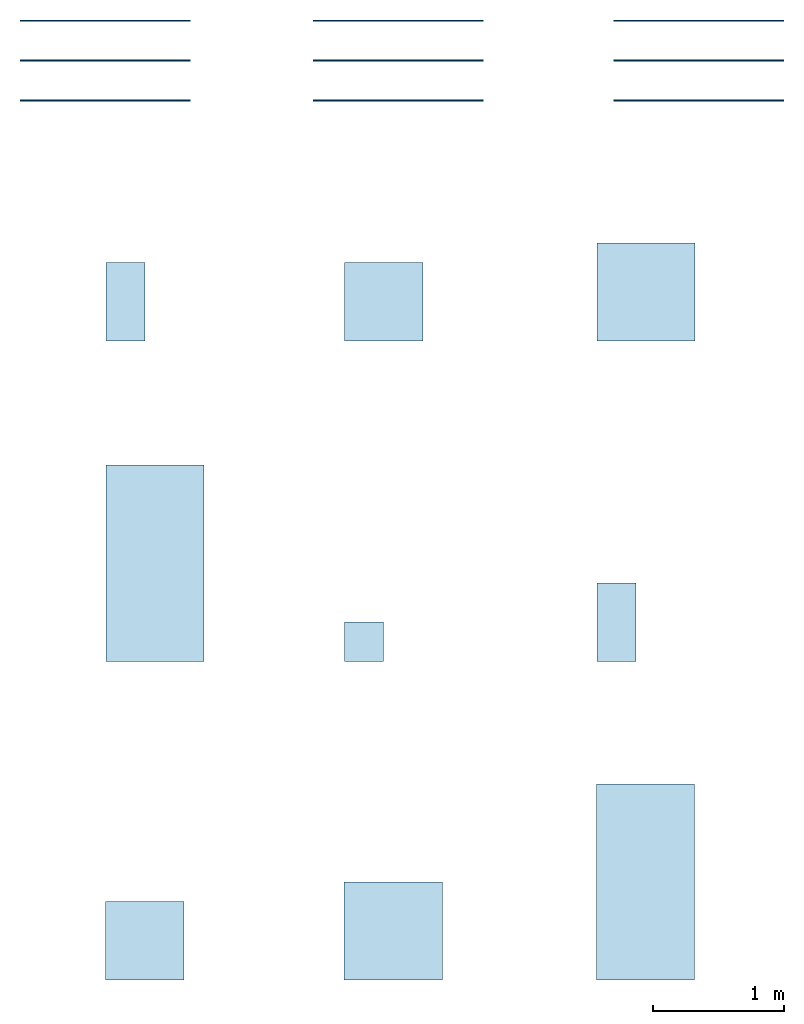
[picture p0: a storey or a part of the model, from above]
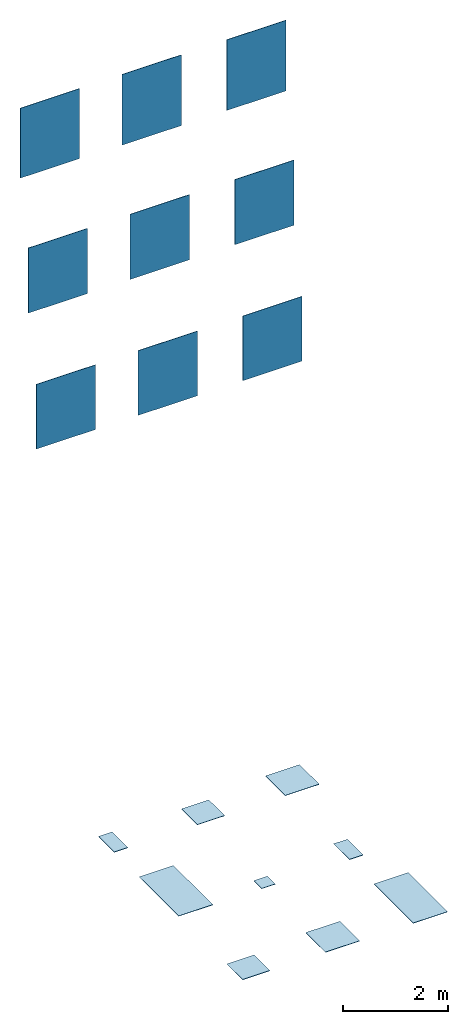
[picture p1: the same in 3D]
Properties of the parts of a building model (IFC2X3)

# File
Description: ViewDefinition [CoordinationView_V2.0]
File name: Project Number
Time: 2021-09-16T11:53:30
Written by: The EXPRESS Data Manager Version 5.02.0100.07 : 28 Aug 2013
Made in: 20190808_0900(x64) - Exporter 19.5.0.0 - Alternate UI 19.5.0.0
Comment: STEP Physical File produced by: The EXPRESS Data Manager Version 5.02.0100.07 : 28 Aug 2013 * Module: EDMstepFileFactory/EDMstandAlone * Creation date: Thu Sep 16 11:53:30 2021 * Host: Davide1988 * Database: C:\Users\DAVIDE~1\AppData\Local\Temp\{9264C9B8-D94B-46D0-A2EC-CCEAC0D1AFE5}\ifc * Database version: 5507 * Database creation date: Thu Sep 16 11:53:26 2021 * Schema: IFC2X3 * Model: DataRepository.ifc * Model creation date: Thu Sep 16 11:53:26 2021 * Header model: DataRepository.ifc_HeaderModel * Header model creation date: Thu Sep 16 11:53:26 2021 * EDMuser: sdai-user * EDMgroup: sdai-group * License ID and type: 5605 : Permanent license. Expiry date: * EDMstepFileFactory options: 020000

# IfcProject, Project Number
LongName: Refin-Blended; Phase: Project Status

# IfcSite, Default
RefLatitude: 51, 30, 0, 549316; RefLongitude: 0, -7, -34, -450321; RefElevation: 0 mm
Pset_ProductRequirements - Category: Project Information

# IfcBuilding
Pset_BuildingCommon - NumberOfStoreys: 1
Pset_ProductRequirements - Category: Project Information

# IfcBuildingStorey: Level:Circle Head - Project Datum, Level 0
LongName: Level 0; Elevation: 0 mm
Pset_AirSideSystemInformation - Name: Level 0
Pset_ProductRequirements - Name: Level 0; Category: Levels

# IfcSlab: Floor:Floor_Tiles_Refin-Prestigio_Onyx-Beige-30x30 NZ91, Floor:Floor_Tiles_Refin-Prestigio_Onyx-Beige-30x30 NZ91:304948
In: Level 0
Type - PredefinedType: FLOOR; Material: Prestigio Onyx-Beige-30x30 NZ91 9 mm, <Unnamed> 1 mm
Type - Pset_ConcreteElementGeneral - FireRating: INERT
Type - Pset_ElementShading - Roughness: 914.4 mm; Color: WHITE
Type - Pset_FireRatingProperties - SurfaceSpreadOfFlame: INERT
Type - Pset_ManufacturerOccurrence - BarCode: N/A; SerialNumber: N/A
Type - Pset_ManufacturerTypeInformation - ArticleNumber: NZ91; ModelReference: NZ91; ModelLabel: BEIGE MOSAICO T LUCIDO R 30X30; Manufacturer: info@refin.it; ProductionYear: N/A
Type - Pset_PrecastConcreteElementGeneral - SerialNumber: N/A
Type - Pset_ProductRequirements - Name: Prestigio Onyx_Beige_Mosaico_T_Lucido_30X30 R; Category: Pr_35_93_96_19:Ceramic tiles
Type - Pset_QuantityTakeOff - Reference: N/A
Type - Pset_ReinforcementBarPitchOfSlab - Description: PORCELAIN STONEWARE TILE; Reference: N/A
Type - Pset_SlabCommon - Reference: N/A; IsExternal: no; AcousticRating: N/A; FireRating: INERT; SurfaceSpreadOfFlame: INERT
Type - Pset_Warranty - WarrantyContent: N/A; Exclusions: N/A
Pset_ProductRequirements - Category: Floors
Pset_SlabCommon - LoadBearing: no; PitchAngle: 0 deg

# IfcSlab: Floor:Floor_Tiles_Refin-Prestigio_Onyx-Beige-30x60 NW01, Floor:Floor_Tiles_Refin-Prestigio_Onyx-Beige-30x60 NW01:304668
In: Level 0
Type - PredefinedType: FLOOR; Material: Prestigio Onyx-Beige-30x60 NW01 9 mm, <Unnamed> 1 mm
Type - Pset_ConcreteElementGeneral - FireRating: INERT
Type - Pset_ElementShading - Roughness: 914.4 mm; Color: IVORY-BEIGE
Type - Pset_FireRatingProperties - SurfaceSpreadOfFlame: INERT
Type - Pset_ManufacturerOccurrence - BarCode: N/A; SerialNumber: N/A
Type - Pset_ManufacturerTypeInformation - ArticleNumber: NW01; ModelReference: NW01; ModelLabel: BEIGE LUCIDO R 30X60; Manufacturer: info@refin.it; ProductionYear: N/A
Type - Pset_PrecastConcreteElementGeneral - SerialNumber: N/A
Type - Pset_ProductRequirements - Name: Prestigio Onyx_Beige_Lucido_30X60 R; Category: Pr_35_93_96_19:Ceramic tiles
Type - Pset_QuantityTakeOff - Reference: N/A
Type - Pset_ReinforcementBarPitchOfSlab - Description: PORCELAIN STONEWARE TILE; Reference: N/A
Type - Pset_SlabCommon - Reference: N/A; IsExternal: no; AcousticRating: N/A; FireRating: INERT; SurfaceSpreadOfFlame: INERT
Type - Pset_Warranty - WarrantyContent: N/A; Exclusions: N/A
Pset_ProductRequirements - Category: Floors
Pset_SlabCommon - LoadBearing: no; PitchAngle: 0 deg

# IfcSlab: Floor:Floor_Tiles_Refin-Prestigio_Onyx-Beige-60x60 NZ95, Floor:Floor_Tiles_Refin-Prestigio_Onyx-Beige-60x60 NZ95:324498
In: Level 0
Type - PredefinedType: FLOOR; Material: Prestigio Onyx-Beige-60x60 NZ95 9 mm, <Unnamed> 1 mm
Type - Pset_ConcreteElementGeneral - FireRating: INERT
Type - Pset_ElementShading - Roughness: 914.4 mm; Color: IVORY-BEIGE
Type - Pset_FireRatingProperties - SurfaceSpreadOfFlame: INERT
Type - Pset_ManufacturerOccurrence - BarCode: N/A; SerialNumber: N/A
Type - Pset_ManufacturerTypeInformation - ArticleNumber: NZ95; ModelReference: NZ95; ModelLabel: BEIGE LUCIDO R 60X60; Manufacturer: info@refin.it; ProductionYear: N/A
Type - Pset_PrecastConcreteElementGeneral - SerialNumber: N/A
Type - Pset_ProductRequirements - Name: Prestigio_Onyx_Beige_Lucido_60X60 R; Category: Pr_35_93_96_19:Ceramic tiles
Type - Pset_QuantityTakeOff - Reference: N/A
Type - Pset_ReinforcementBarPitchOfSlab - Description: PORCELAIN STONEWARE TILE; Reference: N/A
Type - Pset_SlabCommon - Reference: N/A; IsExternal: no; AcousticRating: N/A; FireRating: INERT; SurfaceSpreadOfFlame: INERT
Type - Pset_Warranty - WarrantyContent: N/A; Exclusions: N/A
Pset_ProductRequirements - Category: Floors
Pset_SlabCommon - LoadBearing: no; PitchAngle: 0 deg

# IfcSlab: Floor:Floor_Tiles_Refin-Prestigio_Onyx-Beige-75x150 NV71, Floor:Floor_Tiles_Refin-Prestigio_Onyx-Beige-75x150 NV71:304956
In: Level 0
Type - PredefinedType: FLOOR; Material: Prestigio Onyx-Beige-75x150 NV71 9 mm, <Unnamed> 1 mm
Type - Pset_ConcreteElementGeneral - FireRating: INERT
Type - Pset_ElementShading - Roughness: 914.4 mm; Color: IVORY-BEIGE
Type - Pset_FireRatingProperties - SurfaceSpreadOfFlame: INERT
Type - Pset_ManufacturerOccurrence - BarCode: N/A; SerialNumber: N/A
Type - Pset_ManufacturerTypeInformation - ArticleNumber: NV71; ModelReference: NV71; ModelLabel: BEIGE LUCIDO R 75X150; Manufacturer: info@refin.it; ProductionYear: N/A
Type - Pset_PrecastConcreteElementGeneral - SerialNumber: N/A
Type - Pset_ProductRequirements - Name: Prestigio_Onyx_Beige_Lucido_75X150 R; Category: Pr_35_93_96_19:Ceramic tiles
Type - Pset_QuantityTakeOff - Reference: N/A
Type - Pset_ReinforcementBarPitchOfSlab - Description: PORCELAIN STONEWARE TILE; Reference: N/A
Type - Pset_SlabCommon - Reference: N/A; IsExternal: no; AcousticRating: N/A; FireRating: INERT; SurfaceSpreadOfFlame: INERT
Type - Pset_Warranty - WarrantyContent: N/A; Exclusions: N/A
Pset_ProductRequirements - Category: Floors
Pset_SlabCommon - LoadBearing: no; PitchAngle: 0 deg

# IfcSlab: Floor:Floor_Tiles_Refin-Prestigio_Onyx-Beige-75x75 NZ83, Floor:Floor_Tiles_Refin-Prestigio_Onyx-Beige-75x75 NZ83:285295
In: Level 0
Type - PredefinedType: FLOOR; Material: Prestigio Onyx-Beige-75x75 NZ83 9 mm, <Unnamed> 1 mm
Type - Pset_ConcreteElementGeneral - FireRating: INERT
Type - Pset_ElementShading - Roughness: 914.4 mm; Color: WHITE
Type - Pset_FireRatingProperties - SurfaceSpreadOfFlame: INERT
Type - Pset_ManufacturerOccurrence - BarCode: N/A; SerialNumber: N/A
Type - Pset_ManufacturerTypeInformation - ArticleNumber: NZ83; ModelReference: NZ83; ModelLabel: BEIGE LUCIDO R 75X75; Manufacturer: info@refin.it; ProductionYear: N/A
Type - Pset_PrecastConcreteElementGeneral - SerialNumber: N/A
Type - Pset_ProductRequirements - Name: Prestigio Onyx_Beige_Lucido_75X75 R; Category: Pr_35_93_96_19:Ceramic tiles
Type - Pset_QuantityTakeOff - Reference: N/A
Type - Pset_ReinforcementBarPitchOfSlab - Description: PORCELAIN STONEWARE TILE; Reference: N/A
Type - Pset_SlabCommon - Reference: N/A; IsExternal: no; AcousticRating: N/A; FireRating: INERT; SurfaceSpreadOfFlame: INERT
Type - Pset_Warranty - WarrantyContent: N/A; Exclusions: N/A
Pset_ProductRequirements - Category: Floors
Pset_SlabCommon - LoadBearing: no; PitchAngle: 0 deg

# IfcSlab: Floor:Floor_Tiles_Refin-Prestigio_Onyx-Beige_Soft-30x60 NW06, Floor:Floor_Tiles_Refin-Prestigio_Onyx-Beige_Soft-30x60 NW06:304932
In: Level 0
Type - PredefinedType: FLOOR; Material: Prestigio Onyx-Beige-Soft-30x60 NW06 9 mm, <Unnamed> 1 mm
Type - Pset_ConcreteElementGeneral - FireRating: INERT
Type - Pset_ElementShading - Roughness: 914.4 mm; Color: IVORY-BEIGE
Type - Pset_FireRatingProperties - SurfaceSpreadOfFlame: INERT
Type - Pset_ManufacturerOccurrence - BarCode: N/A; SerialNumber: N/A
Type - Pset_ManufacturerTypeInformation - ArticleNumber: NW06; ModelReference: NW06; ModelLabel: BEIGE SOFT R 30X60; Manufacturer: info@refin.it; ProductionYear: N/A
Type - Pset_PrecastConcreteElementGeneral - SerialNumber: N/A
Type - Pset_ProductRequirements - Name: Prestigio Onyx_Beige_Soft_30X60 R; Category: Pr_35_93_96_19:Ceramic tiles
Type - Pset_QuantityTakeOff - Reference: N/A
Type - Pset_ReinforcementBarPitchOfSlab - Description: PORCELAIN STONEWARE TILE; Reference: N/A
Type - Pset_SlabCommon - Reference: N/A; IsExternal: no; AcousticRating: N/A; FireRating: INERT; SurfaceSpreadOfFlame: INERT
Type - Pset_Warranty - WarrantyContent: N/A; Exclusions: N/A
Pset_ProductRequirements - Category: Floors
Pset_SlabCommon - LoadBearing: no; PitchAngle: 0 deg

# IfcSlab: Floor:Floor_Tiles_Refin-Prestigio_Onyx-Beige_Soft-60x60 NZ98, Floor:Floor_Tiles_Refin-Prestigio_Onyx-Beige_Soft-60x60 NZ98:305509
In: Level 0
Type - PredefinedType: FLOOR; Material: Prestigio Onyx-Beige-Soft-60x60 NZ98 9 mm, <Unnamed> 1 mm
Type - Pset_ConcreteElementGeneral - FireRating: INERT
Type - Pset_ElementShading - Roughness: 914.4 mm; Color: IVORY-BEIGE
Type - Pset_FireRatingProperties - SurfaceSpreadOfFlame: INERT
Type - Pset_ManufacturerOccurrence - BarCode: N/A; SerialNumber: N/A
Type - Pset_ManufacturerTypeInformation - ArticleNumber: NZ98; ModelReference: NZ98; ModelLabel: BEIGE SOFT R 60X60; Manufacturer: info@refin.it; ProductionYear: N/A
Type - Pset_PrecastConcreteElementGeneral - SerialNumber: N/A
Type - Pset_ProductRequirements - Name: Prestigio Onyx_Beige_Soft_60X60 R; Category: Pr_35_93_96_19:Ceramic tiles
Type - Pset_QuantityTakeOff - Reference: N/A
Type - Pset_ReinforcementBarPitchOfSlab - Description: PORCELAIN STONEWARE TILE; Reference: N/A
Type - Pset_SlabCommon - Reference: N/A; IsExternal: no; AcousticRating: N/A; FireRating: INERT; SurfaceSpreadOfFlame: INERT
Type - Pset_Warranty - WarrantyContent: N/A; Exclusions: N/A
Pset_ProductRequirements - Category: Floors
Pset_SlabCommon - LoadBearing: no; PitchAngle: 0 deg

# IfcSlab: Floor:Floor_Tiles_Refin-Prestigio_Onyx-Beige_Soft-75x150 NZ80, Floor:Floor_Tiles_Refin-Prestigio_Onyx-Beige_Soft-75x150 NZ80:339650
In: Level 0
Type - PredefinedType: FLOOR; Material: Prestigio Onyx-Beige-Soft-75x150 NZ80 9 mm, <Unnamed> 1 mm
Type - Pset_ConcreteElementGeneral - FireRating: INERT
Type - Pset_ElementShading - Roughness: 914.4 mm; Color: IVORY-BEIGE
Type - Pset_FireRatingProperties - SurfaceSpreadOfFlame: INERT
Type - Pset_ManufacturerOccurrence - BarCode: N/A; SerialNumber: N/A
Type - Pset_ManufacturerTypeInformation - ArticleNumber: NZ80; ModelReference: NZ80; ModelLabel: BEIGE SOFT R 75X150; Manufacturer: info@refin.it; ProductionYear: N/A
Type - Pset_PrecastConcreteElementGeneral - SerialNumber: N/A
Type - Pset_ProductRequirements - Name: Prestigio Onyx_Beige_Soft_75X150 R; Category: Pr_35_93_96_19:Ceramic tiles
Type - Pset_QuantityTakeOff - Reference: N/A
Type - Pset_ReinforcementBarPitchOfSlab - Description: PORCELAIN STONEWARE TILE; Reference: N/A
Type - Pset_SlabCommon - Reference: N/A; IsExternal: no; AcousticRating: N/A; FireRating: INERT; SurfaceSpreadOfFlame: INERT
Type - Pset_Warranty - WarrantyContent: N/A; Exclusions: N/A
Pset_ProductRequirements - Category: Floors
Pset_SlabCommon - LoadBearing: no; PitchAngle: 0 deg

# IfcSlab: Floor:Floor_Tiles_Refin-Prestigio_Onyx-Beige_Soft-75x75 NZ86, Floor:Floor_Tiles_Refin-Prestigio_Onyx-Beige_Soft-75x75 NZ86:339635
In: Level 0
Type - PredefinedType: FLOOR; Material: Prestigio Onyx-Beige-Soft-75x75 NZ86 9 mm, <Unnamed> 1 mm
Type - Pset_ConcreteElementGeneral - FireRating: INERT
Type - Pset_ElementShading - Roughness: 914.4 mm; Color: IVORY-BEIGE
Type - Pset_FireRatingProperties - SurfaceSpreadOfFlame: INERT
Type - Pset_ManufacturerOccurrence - BarCode: N/A; SerialNumber: N/A
Type - Pset_ManufacturerTypeInformation - ArticleNumber: NZ86; ModelReference: NZ86; ModelLabel: BEIGE SOFT R 75X75; Manufacturer: info@refin.it; ProductionYear: N/A
Type - Pset_PrecastConcreteElementGeneral - SerialNumber: N/A
Type - Pset_ProductRequirements - Name: Prestigio Onyx_Beige_Soft_75X75 R; Category: Pr_35_93_96_19:Ceramic tiles
Type - Pset_QuantityTakeOff - Reference: N/A
Type - Pset_ReinforcementBarPitchOfSlab - Description: PORCELAIN STONEWARE TILE; Reference: N/A
Type - Pset_SlabCommon - Reference: N/A; IsExternal: no; AcousticRating: N/A; FireRating: INERT; SurfaceSpreadOfFlame: INERT
Type - Pset_Warranty - WarrantyContent: N/A; Exclusions: N/A
Pset_ProductRequirements - Category: Floors
Pset_SlabCommon - LoadBearing: no; PitchAngle: 0 deg

# IfcWallStandardCase: Basic Wall:Wall_Tiles_Refin-Prestigio_Onyx-Beige-30x30 NZ91, Basic Wall:Wall_Tiles_Refin-Prestigio_Onyx-Beige-30x30 NZ91:335490
In: Level 0
Type - PredefinedType: STANDARD; Material: <Unnamed> 1 mm, Prestigio Onyx-Beige-30x30 NZ91 9 mm
Type - Pset_ConcreteElementGeneral - FireRating: INERT
Type - Pset_ElementShading - Roughness: 914.4 mm; Color: WHITE
Type - Pset_FireRatingProperties - SurfaceSpreadOfFlame: INERT
Type - Pset_ManufacturerOccurrence - BarCode: N/A; SerialNumber: N/A
Type - Pset_ManufacturerTypeInformation - ArticleNumber: NZ91; ModelReference: NZ91; ModelLabel: BEIGE MOSAICO T LUCIDO R 30X30; Manufacturer: info@refin.it; ProductionYear: N/A
Type - Pset_PrecastConcreteElementGeneral - SerialNumber: N/A
Type - Pset_ProductRequirements - Name: Prestigio Onyx_Beige_Mosaico_T_Lucido_30X30 R; Category: Pr_35_93_96_19:Ceramic tiles
Type - Pset_QuantityTakeOff - Reference: N/A
Type - Pset_ReinforcementBarPitchOfWall - Description: PORCELAIN STONEWARE TILE; Reference: N/A
Type - Pset_WallCommon - Reference: N/A; IsExternal: no; AcousticRating: N/A; FireRating: INERT; SurfaceSpreadOfFlame: INERT
Type - Pset_Warranty - WarrantyContent: N/A; Exclusions: N/A
Pset_ProductRequirements - Category: Walls
Pset_WallCommon - LoadBearing: no; ExtendToStructure: no

# IfcWallStandardCase: Basic Wall:Wall_Tiles_Refin-Prestigio_Onyx-Beige-30x60 NW01, Basic Wall:Wall_Tiles_Refin-Prestigio_Onyx-Beige-30x60 NW01:334895
In: Level 0
Type - PredefinedType: STANDARD; Material: <Unnamed> 1 mm, Prestigio Onyx-Beige-30x60 NW01 9 mm
Type - Pset_ConcreteElementGeneral - FireRating: INERT
Type - Pset_ElementShading - Roughness: 914.4 mm; Color: IVORY-BEIGE
Type - Pset_FireRatingProperties - SurfaceSpreadOfFlame: INERT
Type - Pset_ManufacturerOccurrence - BarCode: N/A; SerialNumber: N/A
Type - Pset_ManufacturerTypeInformation - ArticleNumber: NW01; ModelReference: NW01; ModelLabel: BEIGE LUCIDO R 30X60; Manufacturer: info@refin.it; ProductionYear: N/A
Type - Pset_PrecastConcreteElementGeneral - SerialNumber: N/A
Type - Pset_ProductRequirements - Name: Prestigio Onyx_Beige_Lucido_30X60 R; Category: Pr_35_93_96_19:Ceramic tiles
Type - Pset_QuantityTakeOff - Reference: N/A
Type - Pset_ReinforcementBarPitchOfWall - Description: PORCELAIN STONEWARE TILE; Reference: N/A
Type - Pset_WallCommon - Reference: N/A; IsExternal: no; AcousticRating: N/A; FireRating: INERT; SurfaceSpreadOfFlame: INERT
Type - Pset_Warranty - WarrantyContent: N/A; Exclusions: N/A
Pset_ProductRequirements - Category: Walls
Pset_WallCommon - LoadBearing: no; ExtendToStructure: no

# IfcWallStandardCase: Basic Wall:Wall_Tiles_Refin-Prestigio_Onyx-Beige-60x60 NZ95, Basic Wall:Wall_Tiles_Refin-Prestigio_Onyx-Beige-60x60 NZ95:333696
In: Level 0
Type - PredefinedType: STANDARD; Material: <Unnamed> 1 mm, Prestigio Onyx-Beige-60x60 NZ95 9 mm
Type - Pset_ConcreteElementGeneral - FireRating: INERT
Type - Pset_ElementShading - Roughness: 914.4 mm; Color: IVORY-BEIGE
Type - Pset_FireRatingProperties - SurfaceSpreadOfFlame: INERT
Type - Pset_ManufacturerOccurrence - BarCode: N/A; SerialNumber: N/A
Type - Pset_ManufacturerTypeInformation - ArticleNumber: NZ95; ModelReference: NZ95; ModelLabel: BEIGE LUCIDO R 60X60; Manufacturer: info@refin.it; ProductionYear: N/A
Type - Pset_PrecastConcreteElementGeneral - SerialNumber: N/A
Type - Pset_ProductRequirements - Name: Prestigio_Onyx_Beige_Lucido_60X60 R; Category: Pr_35_93_96_19:Ceramic tiles
Type - Pset_QuantityTakeOff - Reference: N/A
Type - Pset_ReinforcementBarPitchOfWall - Description: PORCELAIN STONEWARE TILE; Reference: N/A
Type - Pset_WallCommon - Reference: N/A; IsExternal: no; AcousticRating: N/A; FireRating: INERT; SurfaceSpreadOfFlame: INERT
Type - Pset_Warranty - WarrantyContent: N/A; Exclusions: N/A
Pset_ProductRequirements - Category: Walls
Pset_WallCommon - LoadBearing: no; ExtendToStructure: no

# IfcWallStandardCase: Basic Wall:Wall_Tiles_Refin-Prestigio_Onyx-Beige-75x150 NV71, Basic Wall:Wall_Tiles_Refin-Prestigio_Onyx-Beige-75x150 NV71:335038
In: Level 0
Type - PredefinedType: STANDARD; Material: <Unnamed> 1 mm, Prestigio Onyx-Beige-75x150 NV71 9 mm
Type - Pset_ConcreteElementGeneral - FireRating: INERT
Type - Pset_ElementShading - Roughness: 914.4 mm; Color: IVORY-BEIGE
Type - Pset_FireRatingProperties - SurfaceSpreadOfFlame: INERT
Type - Pset_ManufacturerOccurrence - BarCode: N/A; SerialNumber: N/A
Type - Pset_ManufacturerTypeInformation - ArticleNumber: NV71; ModelReference: NV71; ModelLabel: BEIGE LUCIDO R 75X150; Manufacturer: info@refin.it; ProductionYear: N/A
Type - Pset_PrecastConcreteElementGeneral - SerialNumber: N/A
Type - Pset_ProductRequirements - Name: Prestigio_Onyx_Beige_Lucido_75X150 R; Category: Pr_35_93_96_19:Ceramic tiles
Type - Pset_QuantityTakeOff - Reference: N/A
Type - Pset_ReinforcementBarPitchOfWall - Description: PORCELAIN STONEWARE TILE; Reference: N/A
Type - Pset_WallCommon - Reference: N/A; IsExternal: no; AcousticRating: N/A; FireRating: INERT; SurfaceSpreadOfFlame: INERT
Type - Pset_Warranty - WarrantyContent: N/A; Exclusions: N/A
Pset_ProductRequirements - Category: Walls
Pset_WallCommon - LoadBearing: no; ExtendToStructure: no

# IfcWallStandardCase: Basic Wall:Wall_Tiles_Refin-Prestigio_Onyx-Beige-75x75 NZ83, Basic Wall:Wall_Tiles_Refin-Prestigio_Onyx-Beige-75x75 NZ83:334553
In: Level 0
Type - PredefinedType: STANDARD; Material: <Unnamed> 1 mm, Prestigio Onyx-Beige-75x75 NZ83 9 mm
Type - Pset_ConcreteElementGeneral - FireRating: INERT
Type - Pset_ElementShading - Roughness: 914.4 mm; Color: WHITE
Type - Pset_FireRatingProperties - SurfaceSpreadOfFlame: INERT
Type - Pset_ManufacturerOccurrence - BarCode: N/A; SerialNumber: N/A
Type - Pset_ManufacturerTypeInformation - ArticleNumber: NZ83; ModelReference: NZ83; ModelLabel: BEIGE LUCIDO R 75X75; Manufacturer: info@refin.it; ProductionYear: N/A
Type - Pset_PrecastConcreteElementGeneral - SerialNumber: N/A
Type - Pset_ProductRequirements - Name: Prestigio Onyx_Beige_Lucido_75X75 R; Category: Pr_35_93_96_19:Ceramic tiles
Type - Pset_QuantityTakeOff - Reference: N/A
Type - Pset_ReinforcementBarPitchOfWall - Description: PORCELAIN STONEWARE TILE; Reference: N/A
Type - Pset_WallCommon - Reference: N/A; IsExternal: no; AcousticRating: N/A; FireRating: INERT; SurfaceSpreadOfFlame: INERT
Type - Pset_Warranty - WarrantyContent: N/A; Exclusions: N/A
Pset_ProductRequirements - Category: Walls
Pset_WallCommon - LoadBearing: no; ExtendToStructure: no

# IfcWallStandardCase: Basic Wall:Wall_Tiles_Refin-Prestigio_Onyx-Beige_Soft_30x60 NW06, Basic Wall:Wall_Tiles_Refin-Prestigio_Onyx-Beige_Soft_30x60 NW06:335882
In: Level 0
Type - PredefinedType: STANDARD; Material: <Unnamed> 1 mm, Prestigio Onyx-Beige-Soft-30x60 NW06 9 mm
Type - Pset_ConcreteElementGeneral - FireRating: INERT
Type - Pset_ElementShading - Roughness: 914.4 mm; Color: IVORY-BEIGE
Type - Pset_FireRatingProperties - SurfaceSpreadOfFlame: INERT
Type - Pset_ManufacturerOccurrence - BarCode: N/A; SerialNumber: N/A
Type - Pset_ManufacturerTypeInformation - ArticleNumber: NW06; ModelReference: NW06; ModelLabel: BEIGE SOFT R 30X60; Manufacturer: info@refin.it; ProductionYear: N/A
Type - Pset_PrecastConcreteElementGeneral - SerialNumber: N/A
Type - Pset_ProductRequirements - Name: Prestigio_Onyx_Beige_Soft_30X60 R; Category: Pr_35_93_96_19:Ceramic tiles
Type - Pset_QuantityTakeOff - Reference: N/A
Type - Pset_ReinforcementBarPitchOfWall - Description: PORCELAIN STONEWARE TILE; Reference: N/A
Type - Pset_WallCommon - Reference: N/A; IsExternal: no; AcousticRating: N/A; FireRating: INERT; SurfaceSpreadOfFlame: INERT
Type - Pset_Warranty - WarrantyContent: N/A; Exclusions: N/A
Pset_ProductRequirements - Category: Walls
Pset_WallCommon - LoadBearing: no; ExtendToStructure: no

# IfcWallStandardCase: Basic Wall:Wall_Tiles_Refin-Prestigio_Onyx-Beige_Soft_60x60 NZ98, Basic Wall:Wall_Tiles_Refin-Prestigio_Onyx-Beige_Soft_60x60 NZ98:336183
In: Level 0
Type - PredefinedType: STANDARD; Material: <Unnamed> 1 mm, Prestigio Onyx-Beige-Soft-60x60 NZ98 9 mm
Type - Pset_ConcreteElementGeneral - FireRating: INERT
Type - Pset_ElementShading - Roughness: 914.4 mm; Color: IVORY-BEIGE
Type - Pset_FireRatingProperties - SurfaceSpreadOfFlame: INERT
Type - Pset_ManufacturerOccurrence - BarCode: N/A; SerialNumber: N/A
Type - Pset_ManufacturerTypeInformation - ArticleNumber: NZ98; ModelReference: NZ98; ModelLabel: BEIGE SOFT R 60X60; Manufacturer: info@refin.it; ProductionYear: N/A
Type - Pset_PrecastConcreteElementGeneral - SerialNumber: N/A
Type - Pset_ProductRequirements - Name: Prestigio_Onyx_Beige_Soft_60X60 R; Category: Pr_35_93_96_19:Ceramic tiles
Type - Pset_QuantityTakeOff - Reference: N/A
Type - Pset_ReinforcementBarPitchOfWall - Description: PORCELAIN STONEWARE TILE; Reference: N/A
Type - Pset_WallCommon - Reference: N/A; IsExternal: no; AcousticRating: N/A; FireRating: INERT; SurfaceSpreadOfFlame: INERT
Type - Pset_Warranty - WarrantyContent: N/A; Exclusions: N/A
Pset_ProductRequirements - Category: Walls
Pset_WallCommon - LoadBearing: no; ExtendToStructure: no

# IfcWallStandardCase: Basic Wall:Wall_Tiles_Refin-Prestigio_Onyx-Beige_Soft_75x150 NZ80, Basic Wall:Wall_Tiles_Refin-Prestigio_Onyx-Beige_Soft_75x150 NZ80:339723
In: Level 0
Type - PredefinedType: STANDARD; Material: <Unnamed> 1 mm, Prestigio Onyx-Beige-Soft-75x150 NZ80 9 mm
Type - Pset_ConcreteElementGeneral - FireRating: INERT
Type - Pset_ElementShading - Roughness: 914.4 mm; Color: IVORY-BEIGE
Type - Pset_FireRatingProperties - SurfaceSpreadOfFlame: INERT
Type - Pset_ManufacturerOccurrence - BarCode: N/A; SerialNumber: N/A
Type - Pset_ManufacturerTypeInformation - ArticleNumber: NZ80; ModelReference: NZ80; ModelLabel: BEIGE SOFT R 75X150; Manufacturer: info@refin.it; ProductionYear: N/A
Type - Pset_PrecastConcreteElementGeneral - SerialNumber: N/A
Type - Pset_ProductRequirements - Name: Prestigio_Onyx_Beige_Soft_75X150 R; Category: Pr_35_93_96_19:Ceramic tiles
Type - Pset_QuantityTakeOff - Reference: N/A
Type - Pset_ReinforcementBarPitchOfWall - Description: PORCELAIN STONEWARE TILE; Reference: N/A
Type - Pset_WallCommon - Reference: N/A; IsExternal: no; AcousticRating: N/A; FireRating: INERT; SurfaceSpreadOfFlame: INERT
Type - Pset_Warranty - WarrantyContent: N/A; Exclusions: N/A
Pset_ProductRequirements - Category: Walls
Pset_WallCommon - LoadBearing: no; ExtendToStructure: no

# IfcWallStandardCase: Basic Wall:Wall_Tiles_Refin-Prestigio_Onyx-Beige_Soft_75x75 NZ86, Basic Wall:Wall_Tiles_Refin-Prestigio_Onyx-Beige_Soft_75x75 NZ86:339715
In: Level 0
Type - PredefinedType: STANDARD; Material: <Unnamed> 1 mm, Prestigio Onyx-Beige-Soft-75x75 NZ86 9 mm
Type - Pset_ConcreteElementGeneral - FireRating: INERT
Type - Pset_ElementShading - Roughness: 914.4 mm; Color: IVORY-BEIGE
Type - Pset_FireRatingProperties - SurfaceSpreadOfFlame: INERT
Type - Pset_ManufacturerOccurrence - BarCode: N/A; SerialNumber: N/A
Type - Pset_ManufacturerTypeInformation - ArticleNumber: NZ86; ModelReference: NZ86; ModelLabel: BEIGE SOFT R 75X75; Manufacturer: info@refin.it; ProductionYear: N/A
Type - Pset_PrecastConcreteElementGeneral - SerialNumber: N/A
Type - Pset_ProductRequirements - Name: Prestigio_Onyx_Beige_Soft_75X75 R; Category: Pr_35_93_96_19:Ceramic tiles
Type - Pset_QuantityTakeOff - Reference: N/A
Type - Pset_ReinforcementBarPitchOfWall - Description: PORCELAIN STONEWARE TILE; Reference: N/A
Type - Pset_WallCommon - Reference: N/A; IsExternal: no; AcousticRating: N/A; FireRating: INERT; SurfaceSpreadOfFlame: INERT
Type - Pset_Warranty - WarrantyContent: N/A; Exclusions: N/A
Pset_ProductRequirements - Category: Walls
Pset_WallCommon - LoadBearing: no; ExtendToStructure: no
